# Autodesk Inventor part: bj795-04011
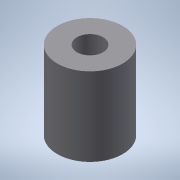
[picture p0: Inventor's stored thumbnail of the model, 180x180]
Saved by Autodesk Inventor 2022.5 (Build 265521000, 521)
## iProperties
Created: 2016-12
Part Number: bj795-04011
Material: 一般
Document SubType Name: Modeling
Designer: imaocorp
Density: 1 g/cm^3
Appearance: 既定
Author: imaocorp
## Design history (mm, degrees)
node "bj795-04011.x_t1"
node "bj795-04011"
node "Base1"
